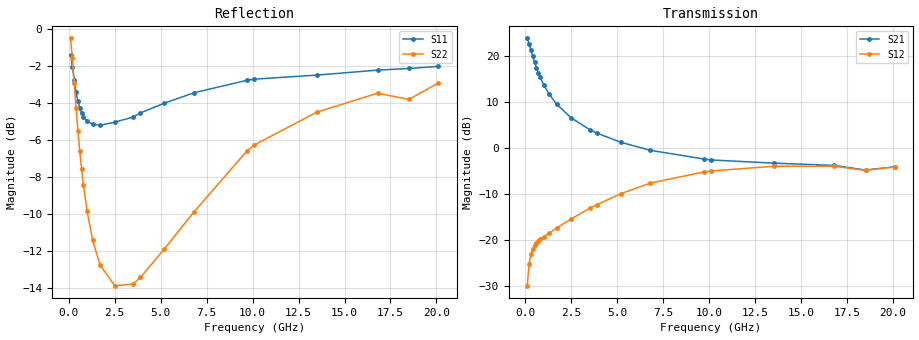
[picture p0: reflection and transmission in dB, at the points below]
!  Infineon Technologies AG
! BFR380L3 , PF131585-7, No.6, Th 09.10.01, soldered on pcb-board, measured with PP GSG850
!  Vce=1.75 V,  Ic=5.0 mA
! Common Emitter S-Parameters:  15. November 2001
#  GHz  S  MA  R  50
! f  S11  S21  S12  S22
! GHz  Mag  Ang  Mag  Ang  Mag  Ang  Mag  Ang
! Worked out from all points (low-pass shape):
!   201 points, 100 MHz to 20.1 GHz, reference 50 ohm
!   highest |S21| = 23.92 dB at 100 MHz (marker M1); lowest = -4.8 dB at 18.5 GHz (marker M2)
!   |S21| within 3 dB of the highest: start of sweep to 333.9 MHz
!   lowest |S11| = -5.2 dB at 1.7 GHz (marker M3), VSWR 3.42, Z = 14.6 - j1.51 ohm
!   |S11| at or under -10 dB: nowhere
!   |S22| runs from -14.0 to -0.5 dB; largest |S21 - S12| = 16
!   S11 on the Smith chart (normalised r, x): 100 MHz: 1.09, -3.37; 400 MHz: 0.35, -0.85; 1 GHz: 0.30, -0.25; 3.9 GHz: 0.29, +0.33; 9.7 GHz: 0.37, +1.12; 20.1 GHz: 0.97, +2.55
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0.1  0.85 -30.2  15.71 160.1  0.03175 74.0  0.9417 -18.9
0.2  0.7895 -56.3  13.72 143.6  0.05429 62.0  0.8309 -34.4
0.3  0.7276 -78.2  11.73 130.9  0.07011 53.2  0.7115 -46.0
0.4  0.6727 -95.4  10.01 121.3  0.08032 47.7  0.6092 -54.5
0.5  0.6364 -109.0  8.617 113.7  0.0873 44.3  0.5288 -61.0
0.6  0.6102 -120.2  7.514 107.8  0.09276 42.3  0.4662 -66.0
0.7  0.5915 -129.2  6.645 102.8  0.0973 41.2  0.4168 -70.0
0.8  0.5787 -136.9  5.932 98.6  0.1013 40.7  0.3776 -73.4
1  0.5617 -149.2  4.886 91.6  0.1085 40.7  0.3212 -78.8
1.3  0.5525 -162.8  3.854 83.3  0.1192 42.1  0.2686 -85.5
1.7  0.5479 -176.2  3.014 74.3  0.1348 44.3  0.23 -93.1
2.5  0.5591 164.6  2.129 59.7  0.1699 47.6  0.2021 -107.7
3.5  0.5768 146.3  1.59 44.6  0.2219 48.6  0.2042 -126.0
3.9  0.5923 140.4  1.456 39.5  0.2427 48.2  0.2128 -134.6
5.2  0.6291 122.9  1.157 24.5  0.3198 43.4  0.254 -157.1
6.8  0.671 104.4  0.9476 10.4  0.4168 34.9  0.3193 175.3
9.7  0.7256 80.1  0.7617 -6.3  0.5503 15.5  0.4679 138.0
10.1  0.7306 77.5  0.7438 -7.9  0.5643 12.8  0.4855 133.4
13.5  0.7493 59.3  0.6871 -21.6  0.6352 -9.3  0.5952 101.0
16.8  0.7729 47.5  0.6486 -32.9  0.635 -25.8  0.6695 78.0
18.5  0.7807 45.7  0.5776 -40.2  0.5712 -34.3  0.6439 72.2
20.1  0.7911 38.4  0.6258 -43.9  0.6239 -39.4  0.7132 61.3
